# Generated by FakeRAM 2.0
VERSION 5.7 ;
BUSBITCHARS "[]" ;
PROPERTYDEFINITIONS
  MACRO width INTEGER ;
  MACRO depth INTEGER ;
  MACRO banks INTEGER ;
END PROPERTYDEFINITIONS
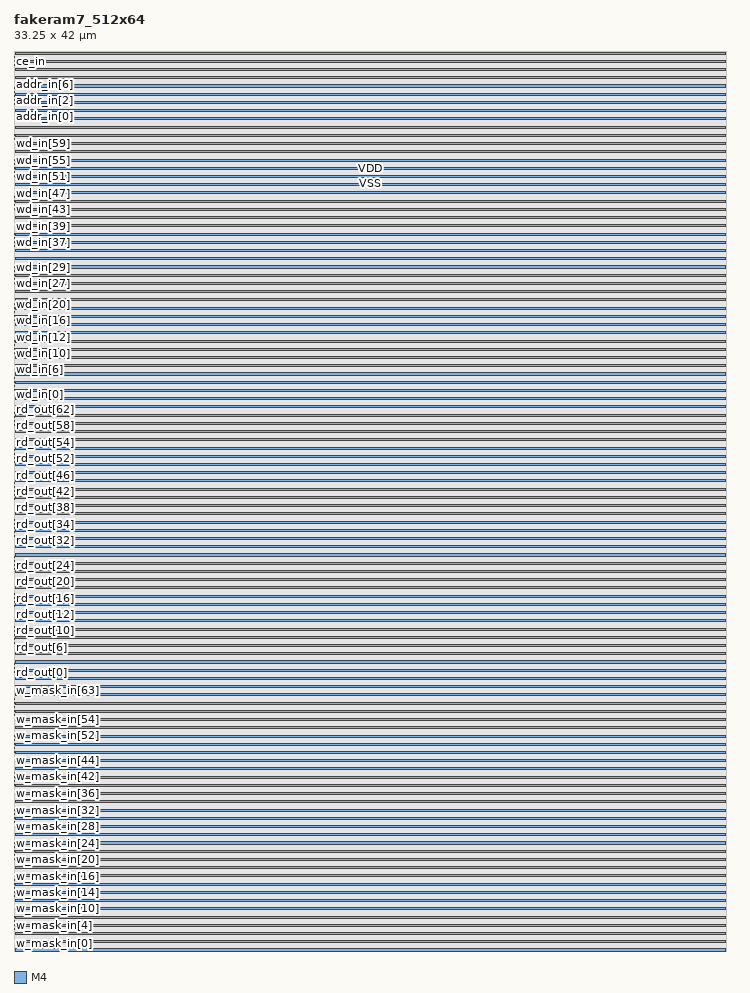
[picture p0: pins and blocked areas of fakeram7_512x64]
MACRO fakeram7_512x64
  PROPERTY width 64 ;
  PROPERTY depth 512 ;
  PROPERTY banks 4 ;
  FOREIGN fakeram7_512x64 0 0 ;
  SYMMETRY X Y ;
  SIZE 33.250 BY 42.000 ;
  CLASS BLOCK ;
  PIN w_mask_in[0]
    DIRECTION INPUT ;
    USE SIGNAL ;
    SHAPE ABUTMENT ;
    PORT
      LAYER M4 ;
      RECT 0.000 0.048 0.024 0.072 ;
    END
  END w_mask_in[0]
  PIN w_mask_in[1]
    DIRECTION INPUT ;
    USE SIGNAL ;
    SHAPE ABUTMENT ;
    PORT
      LAYER M4 ;
      RECT 0.000 0.240 0.024 0.264 ;
    END
  END w_mask_in[1]
  PIN w_mask_in[2]
    DIRECTION INPUT ;
    USE SIGNAL ;
    SHAPE ABUTMENT ;
    PORT
      LAYER M4 ;
      RECT 0.000 0.432 0.024 0.456 ;
    END
  END w_mask_in[2]
  PIN w_mask_in[3]
    DIRECTION INPUT ;
    USE SIGNAL ;
    SHAPE ABUTMENT ;
    PORT
      LAYER M4 ;
      RECT 0.000 0.624 0.024 0.648 ;
    END
  END w_mask_in[3]
  PIN w_mask_in[4]
    DIRECTION INPUT ;
    USE SIGNAL ;
    SHAPE ABUTMENT ;
    PORT
      LAYER M4 ;
      RECT 0.000 0.816 0.024 0.840 ;
    END
  END w_mask_in[4]
  PIN w_mask_in[5]
    DIRECTION INPUT ;
    USE SIGNAL ;
    SHAPE ABUTMENT ;
    PORT
      LAYER M4 ;
      RECT 0.000 1.008 0.024 1.032 ;
    END
  END w_mask_in[5]
  PIN w_mask_in[6]
    DIRECTION INPUT ;
    USE SIGNAL ;
    SHAPE ABUTMENT ;
    PORT
      LAYER M4 ;
      RECT 0.000 1.200 0.024 1.224 ;
    END
  END w_mask_in[6]
  PIN w_mask_in[7]
    DIRECTION INPUT ;
    USE SIGNAL ;
    SHAPE ABUTMENT ;
    PORT
      LAYER M4 ;
      RECT 0.000 1.392 0.024 1.416 ;
    END
  END w_mask_in[7]
  PIN w_mask_in[8]
    DIRECTION INPUT ;
    USE SIGNAL ;
    SHAPE ABUTMENT ;
    PORT
      LAYER M4 ;
      RECT 0.000 1.584 0.024 1.608 ;
    END
  END w_mask_in[8]
  PIN w_mask_in[9]
    DIRECTION INPUT ;
    USE SIGNAL ;
    SHAPE ABUTMENT ;
    PORT
      LAYER M4 ;
      RECT 0.000 1.776 0.024 1.800 ;
    END
  END w_mask_in[9]
  PIN w_mask_in[10]
    DIRECTION INPUT ;
    USE SIGNAL ;
    SHAPE ABUTMENT ;
    PORT
      LAYER M4 ;
      RECT 0.000 1.968 0.024 1.992 ;
    END
  END w_mask_in[10]
  PIN w_mask_in[11]
    DIRECTION INPUT ;
    USE SIGNAL ;
    SHAPE ABUTMENT ;
    PORT
      LAYER M4 ;
      RECT 0.000 2.160 0.024 2.184 ;
    END
  END w_mask_in[11]
  PIN w_mask_in[12]
    DIRECTION INPUT ;
    USE SIGNAL ;
    SHAPE ABUTMENT ;
    PORT
      LAYER M4 ;
      RECT 0.000 2.352 0.024 2.376 ;
    END
  END w_mask_in[12]
  PIN w_mask_in[13]
    DIRECTION INPUT ;
    USE SIGNAL ;
    SHAPE ABUTMENT ;
    PORT
      LAYER M4 ;
      RECT 0.000 2.544 0.024 2.568 ;
    END
  END w_mask_in[13]
  PIN w_mask_in[14]
    DIRECTION INPUT ;
    USE SIGNAL ;
    SHAPE ABUTMENT ;
    PORT
      LAYER M4 ;
      RECT 0.000 2.736 0.024 2.760 ;
    END
  END w_mask_in[14]
  PIN w_mask_in[15]
    DIRECTION INPUT ;
    USE SIGNAL ;
    SHAPE ABUTMENT ;
    PORT
      LAYER M4 ;
      RECT 0.000 2.928 0.024 2.952 ;
    END
  END w_mask_in[15]
  PIN w_mask_in[16]
    DIRECTION INPUT ;
    USE SIGNAL ;
    SHAPE ABUTMENT ;
    PORT
      LAYER M4 ;
      RECT 0.000 3.120 0.024 3.144 ;
    END
  END w_mask_in[16]
  PIN w_mask_in[17]
    DIRECTION INPUT ;
    USE SIGNAL ;
    SHAPE ABUTMENT ;
    PORT
      LAYER M4 ;
      RECT 0.000 3.312 0.024 3.336 ;
    END
  END w_mask_in[17]
  PIN w_mask_in[18]
    DIRECTION INPUT ;
    USE SIGNAL ;
    SHAPE ABUTMENT ;
    PORT
      LAYER M4 ;
      RECT 0.000 3.504 0.024 3.528 ;
    END
  END w_mask_in[18]
  PIN w_mask_in[19]
    DIRECTION INPUT ;
    USE SIGNAL ;
    SHAPE ABUTMENT ;
    PORT
      LAYER M4 ;
      RECT 0.000 3.696 0.024 3.720 ;
    END
  END w_mask_in[19]
  PIN w_mask_in[20]
    DIRECTION INPUT ;
    USE SIGNAL ;
    SHAPE ABUTMENT ;
    PORT
      LAYER M4 ;
      RECT 0.000 3.888 0.024 3.912 ;
    END
  END w_mask_in[20]
  PIN w_mask_in[21]
    DIRECTION INPUT ;
    USE SIGNAL ;
    SHAPE ABUTMENT ;
    PORT
      LAYER M4 ;
      RECT 0.000 4.080 0.024 4.104 ;
    END
  END w_mask_in[21]
  PIN w_mask_in[22]
    DIRECTION INPUT ;
    USE SIGNAL ;
    SHAPE ABUTMENT ;
    PORT
      LAYER M4 ;
      RECT 0.000 4.272 0.024 4.296 ;
    END
  END w_mask_in[22]
  PIN w_mask_in[23]
    DIRECTION INPUT ;
    USE SIGNAL ;
    SHAPE ABUTMENT ;
    PORT
      LAYER M4 ;
      RECT 0.000 4.464 0.024 4.488 ;
    END
  END w_mask_in[23]
  PIN w_mask_in[24]
    DIRECTION INPUT ;
    USE SIGNAL ;
    SHAPE ABUTMENT ;
    PORT
      LAYER M4 ;
      RECT 0.000 4.656 0.024 4.680 ;
    END
  END w_mask_in[24]
  PIN w_mask_in[25]
    DIRECTION INPUT ;
    USE SIGNAL ;
    SHAPE ABUTMENT ;
    PORT
      LAYER M4 ;
      RECT 0.000 4.848 0.024 4.872 ;
    END
  END w_mask_in[25]
  PIN w_mask_in[26]
    DIRECTION INPUT ;
    USE SIGNAL ;
    SHAPE ABUTMENT ;
    PORT
      LAYER M4 ;
      RECT 0.000 5.040 0.024 5.064 ;
    END
  END w_mask_in[26]
  PIN w_mask_in[27]
    DIRECTION INPUT ;
    USE SIGNAL ;
    SHAPE ABUTMENT ;
    PORT
      LAYER M4 ;
      RECT 0.000 5.232 0.024 5.256 ;
    END
  END w_mask_in[27]
  PIN w_mask_in[28]
    DIRECTION INPUT ;
    USE SIGNAL ;
    SHAPE ABUTMENT ;
    PORT
      LAYER M4 ;
      RECT 0.000 5.424 0.024 5.448 ;
    END
  END w_mask_in[28]
  PIN w_mask_in[29]
    DIRECTION INPUT ;
    USE SIGNAL ;
    SHAPE ABUTMENT ;
    PORT
      LAYER M4 ;
      RECT 0.000 5.616 0.024 5.640 ;
    END
  END w_mask_in[29]
  PIN w_mask_in[30]
    DIRECTION INPUT ;
    USE SIGNAL ;
    SHAPE ABUTMENT ;
    PORT
      LAYER M4 ;
      RECT 0.000 5.808 0.024 5.832 ;
    END
  END w_mask_in[30]
  PIN w_mask_in[31]
    DIRECTION INPUT ;
    USE SIGNAL ;
    SHAPE ABUTMENT ;
    PORT
      LAYER M4 ;
      RECT 0.000 6.000 0.024 6.024 ;
    END
  END w_mask_in[31]
  PIN w_mask_in[32]
    DIRECTION INPUT ;
    USE SIGNAL ;
    SHAPE ABUTMENT ;
    PORT
      LAYER M4 ;
      RECT 0.000 6.192 0.024 6.216 ;
    END
  END w_mask_in[32]
  PIN w_mask_in[33]
    DIRECTION INPUT ;
    USE SIGNAL ;
    SHAPE ABUTMENT ;
    PORT
      LAYER M4 ;
      RECT 0.000 6.384 0.024 6.408 ;
    END
  END w_mask_in[33]
  PIN w_mask_in[34]
    DIRECTION INPUT ;
    USE SIGNAL ;
    SHAPE ABUTMENT ;
    PORT
      LAYER M4 ;
      RECT 0.000 6.576 0.024 6.600 ;
    END
  END w_mask_in[34]
  PIN w_mask_in[35]
    DIRECTION INPUT ;
    USE SIGNAL ;
    SHAPE ABUTMENT ;
    PORT
      LAYER M4 ;
      RECT 0.000 6.768 0.024 6.792 ;
    END
  END w_mask_in[35]
  PIN w_mask_in[36]
    DIRECTION INPUT ;
    USE SIGNAL ;
    SHAPE ABUTMENT ;
    PORT
      LAYER M4 ;
      RECT 0.000 6.960 0.024 6.984 ;
    END
  END w_mask_in[36]
  PIN w_mask_in[37]
    DIRECTION INPUT ;
    USE SIGNAL ;
    SHAPE ABUTMENT ;
    PORT
      LAYER M4 ;
      RECT 0.000 7.152 0.024 7.176 ;
    END
  END w_mask_in[37]
  PIN w_mask_in[38]
    DIRECTION INPUT ;
    USE SIGNAL ;
    SHAPE ABUTMENT ;
    PORT
      LAYER M4 ;
      RECT 0.000 7.344 0.024 7.368 ;
    END
  END w_mask_in[38]
  PIN w_mask_in[39]
    DIRECTION INPUT ;
    USE SIGNAL ;
    SHAPE ABUTMENT ;
    PORT
      LAYER M4 ;
      RECT 0.000 7.536 0.024 7.560 ;
    END
  END w_mask_in[39]
  PIN w_mask_in[40]
    DIRECTION INPUT ;
    USE SIGNAL ;
    SHAPE ABUTMENT ;
    PORT
      LAYER M4 ;
      RECT 0.000 7.728 0.024 7.752 ;
    END
  END w_mask_in[40]
  PIN w_mask_in[41]
    DIRECTION INPUT ;
    USE SIGNAL ;
    SHAPE ABUTMENT ;
    PORT
      LAYER M4 ;
      RECT 0.000 7.920 0.024 7.944 ;
    END
  END w_mask_in[41]
  PIN w_mask_in[42]
    DIRECTION INPUT ;
    USE SIGNAL ;
    SHAPE ABUTMENT ;
    PORT
      LAYER M4 ;
      RECT 0.000 8.112 0.024 8.136 ;
    END
  END w_mask_in[42]
  PIN w_mask_in[43]
    DIRECTION INPUT ;
    USE SIGNAL ;
    SHAPE ABUTMENT ;
    PORT
      LAYER M4 ;
      RECT 0.000 8.304 0.024 8.328 ;
    END
  END w_mask_in[43]
  PIN w_mask_in[44]
    DIRECTION INPUT ;
    USE SIGNAL ;
    SHAPE ABUTMENT ;
    PORT
      LAYER M4 ;
      RECT 0.000 8.496 0.024 8.520 ;
    END
  END w_mask_in[44]
  PIN w_mask_in[45]
    DIRECTION INPUT ;
    USE SIGNAL ;
    SHAPE ABUTMENT ;
    PORT
      LAYER M4 ;
      RECT 0.000 8.688 0.024 8.712 ;
    END
  END w_mask_in[45]
  PIN w_mask_in[46]
    DIRECTION INPUT ;
    USE SIGNAL ;
    SHAPE ABUTMENT ;
    PORT
      LAYER M4 ;
      RECT 0.000 8.880 0.024 8.904 ;
    END
  END w_mask_in[46]
  PIN w_mask_in[47]
    DIRECTION INPUT ;
    USE SIGNAL ;
    SHAPE ABUTMENT ;
    PORT
      LAYER M4 ;
      RECT 0.000 9.072 0.024 9.096 ;
    END
  END w_mask_in[47]
  PIN w_mask_in[48]
    DIRECTION INPUT ;
    USE SIGNAL ;
    SHAPE ABUTMENT ;
    PORT
      LAYER M4 ;
      RECT 0.000 9.264 0.024 9.288 ;
    END
  END w_mask_in[48]
  PIN w_mask_in[49]
    DIRECTION INPUT ;
    USE SIGNAL ;
    SHAPE ABUTMENT ;
    PORT
      LAYER M4 ;
      RECT 0.000 9.456 0.024 9.480 ;
    END
  END w_mask_in[49]
  PIN w_mask_in[50]
    DIRECTION INPUT ;
    USE SIGNAL ;
    SHAPE ABUTMENT ;
    PORT
      LAYER M4 ;
      RECT 0.000 9.648 0.024 9.672 ;
    END
  END w_mask_in[50]
  PIN w_mask_in[51]
    DIRECTION INPUT ;
    USE SIGNAL ;
    SHAPE ABUTMENT ;
    PORT
      LAYER M4 ;
      RECT 0.000 9.840 0.024 9.864 ;
    END
  END w_mask_in[51]
  PIN w_mask_in[52]
    DIRECTION INPUT ;
    USE SIGNAL ;
    SHAPE ABUTMENT ;
    PORT
      LAYER M4 ;
      RECT 0.000 10.032 0.024 10.056 ;
    END
  END w_mask_in[52]
  PIN w_mask_in[53]
    DIRECTION INPUT ;
    USE SIGNAL ;
    SHAPE ABUTMENT ;
    PORT
      LAYER M4 ;
      RECT 0.000 10.224 0.024 10.248 ;
    END
  END w_mask_in[53]
  PIN w_mask_in[54]
    DIRECTION INPUT ;
    USE SIGNAL ;
    SHAPE ABUTMENT ;
    PORT
      LAYER M4 ;
      RECT 0.000 10.416 0.024 10.440 ;
    END
  END w_mask_in[54]
  PIN w_mask_in[55]
    DIRECTION INPUT ;
    USE SIGNAL ;
    SHAPE ABUTMENT ;
    PORT
      LAYER M4 ;
      RECT 0.000 10.608 0.024 10.632 ;
    END
  END w_mask_in[55]
  PIN w_mask_in[56]
    DIRECTION INPUT ;
    USE SIGNAL ;
    SHAPE ABUTMENT ;
    PORT
      LAYER M4 ;
      RECT 0.000 10.800 0.024 10.824 ;
    END
  END w_mask_in[56]
  PIN w_mask_in[57]
    DIRECTION INPUT ;
    USE SIGNAL ;
    SHAPE ABUTMENT ;
    PORT
      LAYER M4 ;
      RECT 0.000 10.992 0.024 11.016 ;
    END
  END w_mask_in[57]
  PIN w_mask_in[58]
    DIRECTION INPUT ;
    USE SIGNAL ;
    SHAPE ABUTMENT ;
    PORT
      LAYER M4 ;
      RECT 0.000 11.184 0.024 11.208 ;
    END
  END w_mask_in[58]
  PIN w_mask_in[59]
    DIRECTION INPUT ;
    USE SIGNAL ;
    SHAPE ABUTMENT ;
    PORT
      LAYER M4 ;
      RECT 0.000 11.376 0.024 11.400 ;
    END
  END w_mask_in[59]
  PIN w_mask_in[60]
    DIRECTION INPUT ;
    USE SIGNAL ;
    SHAPE ABUTMENT ;
    PORT
      LAYER M4 ;
      RECT 0.000 11.568 0.024 11.592 ;
    END
  END w_mask_in[60]
  PIN w_mask_in[61]
    DIRECTION INPUT ;
    USE SIGNAL ;
    SHAPE ABUTMENT ;
    PORT
      LAYER M4 ;
      RECT 0.000 11.760 0.024 11.784 ;
    END
  END w_mask_in[61]
  PIN w_mask_in[62]
    DIRECTION INPUT ;
    USE SIGNAL ;
    SHAPE ABUTMENT ;
    PORT
      LAYER M4 ;
      RECT 0.000 11.952 0.024 11.976 ;
    END
  END w_mask_in[62]
  PIN w_mask_in[63]
    DIRECTION INPUT ;
    USE SIGNAL ;
    SHAPE ABUTMENT ;
    PORT
      LAYER M4 ;
      RECT 0.000 12.144 0.024 12.168 ;
    END
  END w_mask_in[63]
  PIN rd_out[0]
    DIRECTION OUTPUT ;
    USE SIGNAL ;
    SHAPE ABUTMENT ;
    PORT
      LAYER M4 ;
      RECT 0.000 13.008 0.024 13.032 ;
    END
  END rd_out[0]
  PIN rd_out[1]
    DIRECTION OUTPUT ;
    USE SIGNAL ;
    SHAPE ABUTMENT ;
    PORT
      LAYER M4 ;
      RECT 0.000 13.200 0.024 13.224 ;
    END
  END rd_out[1]
  PIN rd_out[2]
    DIRECTION OUTPUT ;
    USE SIGNAL ;
    SHAPE ABUTMENT ;
    PORT
      LAYER M4 ;
      RECT 0.000 13.392 0.024 13.416 ;
    END
  END rd_out[2]
  PIN rd_out[3]
    DIRECTION OUTPUT ;
    USE SIGNAL ;
    SHAPE ABUTMENT ;
    PORT
      LAYER M4 ;
      RECT 0.000 13.584 0.024 13.608 ;
    END
  END rd_out[3]
  PIN rd_out[4]
    DIRECTION OUTPUT ;
    USE SIGNAL ;
    SHAPE ABUTMENT ;
    PORT
      LAYER M4 ;
      RECT 0.000 13.776 0.024 13.800 ;
    END
  END rd_out[4]
  PIN rd_out[5]
    DIRECTION OUTPUT ;
    USE SIGNAL ;
    SHAPE ABUTMENT ;
    PORT
      LAYER M4 ;
      RECT 0.000 13.968 0.024 13.992 ;
    END
  END rd_out[5]
  PIN rd_out[6]
    DIRECTION OUTPUT ;
    USE SIGNAL ;
    SHAPE ABUTMENT ;
    PORT
      LAYER M4 ;
      RECT 0.000 14.160 0.024 14.184 ;
    END
  END rd_out[6]
  PIN rd_out[7]
    DIRECTION OUTPUT ;
    USE SIGNAL ;
    SHAPE ABUTMENT ;
    PORT
      LAYER M4 ;
      RECT 0.000 14.352 0.024 14.376 ;
    END
  END rd_out[7]
  PIN rd_out[8]
    DIRECTION OUTPUT ;
    USE SIGNAL ;
    SHAPE ABUTMENT ;
    PORT
      LAYER M4 ;
      RECT 0.000 14.544 0.024 14.568 ;
    END
  END rd_out[8]
  PIN rd_out[9]
    DIRECTION OUTPUT ;
    USE SIGNAL ;
    SHAPE ABUTMENT ;
    PORT
      LAYER M4 ;
      RECT 0.000 14.736 0.024 14.760 ;
    END
  END rd_out[9]
  PIN rd_out[10]
    DIRECTION OUTPUT ;
    USE SIGNAL ;
    SHAPE ABUTMENT ;
    PORT
      LAYER M4 ;
      RECT 0.000 14.928 0.024 14.952 ;
    END
  END rd_out[10]
  PIN rd_out[11]
    DIRECTION OUTPUT ;
    USE SIGNAL ;
    SHAPE ABUTMENT ;
    PORT
      LAYER M4 ;
      RECT 0.000 15.120 0.024 15.144 ;
    END
  END rd_out[11]
  PIN rd_out[12]
    DIRECTION OUTPUT ;
    USE SIGNAL ;
    SHAPE ABUTMENT ;
    PORT
      LAYER M4 ;
      RECT 0.000 15.312 0.024 15.336 ;
    END
  END rd_out[12]
  PIN rd_out[13]
    DIRECTION OUTPUT ;
    USE SIGNAL ;
    SHAPE ABUTMENT ;
    PORT
      LAYER M4 ;
      RECT 0.000 15.504 0.024 15.528 ;
    END
  END rd_out[13]
  PIN rd_out[14]
    DIRECTION OUTPUT ;
    USE SIGNAL ;
    SHAPE ABUTMENT ;
    PORT
      LAYER M4 ;
      RECT 0.000 15.696 0.024 15.720 ;
    END
  END rd_out[14]
  PIN rd_out[15]
    DIRECTION OUTPUT ;
    USE SIGNAL ;
    SHAPE ABUTMENT ;
    PORT
      LAYER M4 ;
      RECT 0.000 15.888 0.024 15.912 ;
    END
  END rd_out[15]
  PIN rd_out[16]
    DIRECTION OUTPUT ;
    USE SIGNAL ;
    SHAPE ABUTMENT ;
    PORT
      LAYER M4 ;
      RECT 0.000 16.080 0.024 16.104 ;
    END
  END rd_out[16]
  PIN rd_out[17]
    DIRECTION OUTPUT ;
    USE SIGNAL ;
    SHAPE ABUTMENT ;
    PORT
      LAYER M4 ;
      RECT 0.000 16.272 0.024 16.296 ;
    END
  END rd_out[17]
  PIN rd_out[18]
    DIRECTION OUTPUT ;
    USE SIGNAL ;
    SHAPE ABUTMENT ;
    PORT
      LAYER M4 ;
      RECT 0.000 16.464 0.024 16.488 ;
    END
  END rd_out[18]
  PIN rd_out[19]
    DIRECTION OUTPUT ;
    USE SIGNAL ;
    SHAPE ABUTMENT ;
    PORT
      LAYER M4 ;
      RECT 0.000 16.656 0.024 16.680 ;
    END
  END rd_out[19]
  PIN rd_out[20]
    DIRECTION OUTPUT ;
    USE SIGNAL ;
    SHAPE ABUTMENT ;
    PORT
      LAYER M4 ;
      RECT 0.000 16.848 0.024 16.872 ;
    END
  END rd_out[20]
  PIN rd_out[21]
    DIRECTION OUTPUT ;
    USE SIGNAL ;
    SHAPE ABUTMENT ;
    PORT
      LAYER M4 ;
      RECT 0.000 17.040 0.024 17.064 ;
    END
  END rd_out[21]
  PIN rd_out[22]
    DIRECTION OUTPUT ;
    USE SIGNAL ;
    SHAPE ABUTMENT ;
    PORT
      LAYER M4 ;
      RECT 0.000 17.232 0.024 17.256 ;
    END
  END rd_out[22]
  PIN rd_out[23]
    DIRECTION OUTPUT ;
    USE SIGNAL ;
    SHAPE ABUTMENT ;
    PORT
      LAYER M4 ;
      RECT 0.000 17.424 0.024 17.448 ;
    END
  END rd_out[23]
  PIN rd_out[24]
    DIRECTION OUTPUT ;
    USE SIGNAL ;
    SHAPE ABUTMENT ;
    PORT
      LAYER M4 ;
      RECT 0.000 17.616 0.024 17.640 ;
    END
  END rd_out[24]
  PIN rd_out[25]
    DIRECTION OUTPUT ;
    USE SIGNAL ;
    SHAPE ABUTMENT ;
    PORT
      LAYER M4 ;
      RECT 0.000 17.808 0.024 17.832 ;
    END
  END rd_out[25]
  PIN rd_out[26]
    DIRECTION OUTPUT ;
    USE SIGNAL ;
    SHAPE ABUTMENT ;
    PORT
      LAYER M4 ;
      RECT 0.000 18.000 0.024 18.024 ;
    END
  END rd_out[26]
  PIN rd_out[27]
    DIRECTION OUTPUT ;
    USE SIGNAL ;
    SHAPE ABUTMENT ;
    PORT
      LAYER M4 ;
      RECT 0.000 18.192 0.024 18.216 ;
    END
  END rd_out[27]
  PIN rd_out[28]
    DIRECTION OUTPUT ;
    USE SIGNAL ;
    SHAPE ABUTMENT ;
    PORT
      LAYER M4 ;
      RECT 0.000 18.384 0.024 18.408 ;
    END
  END rd_out[28]
  PIN rd_out[29]
    DIRECTION OUTPUT ;
    USE SIGNAL ;
    SHAPE ABUTMENT ;
    PORT
      LAYER M4 ;
      RECT 0.000 18.576 0.024 18.600 ;
    END
  END rd_out[29]
  PIN rd_out[30]
    DIRECTION OUTPUT ;
    USE SIGNAL ;
    SHAPE ABUTMENT ;
    PORT
      LAYER M4 ;
      RECT 0.000 18.768 0.024 18.792 ;
    END
  END rd_out[30]
  PIN rd_out[31]
    DIRECTION OUTPUT ;
    USE SIGNAL ;
    SHAPE ABUTMENT ;
    PORT
      LAYER M4 ;
      RECT 0.000 18.960 0.024 18.984 ;
    END
  END rd_out[31]
  PIN rd_out[32]
    DIRECTION OUTPUT ;
    USE SIGNAL ;
    SHAPE ABUTMENT ;
    PORT
      LAYER M4 ;
      RECT 0.000 19.152 0.024 19.176 ;
    END
  END rd_out[32]
  PIN rd_out[33]
    DIRECTION OUTPUT ;
    USE SIGNAL ;
    SHAPE ABUTMENT ;
    PORT
      LAYER M4 ;
      RECT 0.000 19.344 0.024 19.368 ;
    END
  END rd_out[33]
  PIN rd_out[34]
    DIRECTION OUTPUT ;
    USE SIGNAL ;
    SHAPE ABUTMENT ;
    PORT
      LAYER M4 ;
      RECT 0.000 19.536 0.024 19.560 ;
    END
  END rd_out[34]
  PIN rd_out[35]
    DIRECTION OUTPUT ;
    USE SIGNAL ;
    SHAPE ABUTMENT ;
    PORT
      LAYER M4 ;
      RECT 0.000 19.728 0.024 19.752 ;
    END
  END rd_out[35]
  PIN rd_out[36]
    DIRECTION OUTPUT ;
    USE SIGNAL ;
    SHAPE ABUTMENT ;
    PORT
      LAYER M4 ;
      RECT 0.000 19.920 0.024 19.944 ;
    END
  END rd_out[36]
  PIN rd_out[37]
    DIRECTION OUTPUT ;
    USE SIGNAL ;
    SHAPE ABUTMENT ;
    PORT
      LAYER M4 ;
      RECT 0.000 20.112 0.024 20.136 ;
    END
  END rd_out[37]
  PIN rd_out[38]
    DIRECTION OUTPUT ;
    USE SIGNAL ;
    SHAPE ABUTMENT ;
    PORT
      LAYER M4 ;
      RECT 0.000 20.304 0.024 20.328 ;
    END
  END rd_out[38]
  PIN rd_out[39]
    DIRECTION OUTPUT ;
    USE SIGNAL ;
    SHAPE ABUTMENT ;
    PORT
      LAYER M4 ;
      RECT 0.000 20.496 0.024 20.520 ;
    END
  END rd_out[39]
  PIN rd_out[40]
    DIRECTION OUTPUT ;
    USE SIGNAL ;
    SHAPE ABUTMENT ;
    PORT
      LAYER M4 ;
      RECT 0.000 20.688 0.024 20.712 ;
    END
  END rd_out[40]
  PIN rd_out[41]
    DIRECTION OUTPUT ;
    USE SIGNAL ;
    SHAPE ABUTMENT ;
    PORT
      LAYER M4 ;
      RECT 0.000 20.880 0.024 20.904 ;
    END
  END rd_out[41]
  PIN rd_out[42]
    DIRECTION OUTPUT ;
    USE SIGNAL ;
    SHAPE ABUTMENT ;
    PORT
      LAYER M4 ;
      RECT 0.000 21.072 0.024 21.096 ;
    END
  END rd_out[42]
  PIN rd_out[43]
    DIRECTION OUTPUT ;
    USE SIGNAL ;
    SHAPE ABUTMENT ;
    PORT
      LAYER M4 ;
      RECT 0.000 21.264 0.024 21.288 ;
    END
  END rd_out[43]
  PIN rd_out[44]
    DIRECTION OUTPUT ;
    USE SIGNAL ;
    SHAPE ABUTMENT ;
    PORT
      LAYER M4 ;
      RECT 0.000 21.456 0.024 21.480 ;
    END
  END rd_out[44]
  PIN rd_out[45]
    DIRECTION OUTPUT ;
    USE SIGNAL ;
    SHAPE ABUTMENT ;
    PORT
      LAYER M4 ;
      RECT 0.000 21.648 0.024 21.672 ;
    END
  END rd_out[45]
  PIN rd_out[46]
    DIRECTION OUTPUT ;
    USE SIGNAL ;
    SHAPE ABUTMENT ;
    PORT
      LAYER M4 ;
      RECT 0.000 21.840 0.024 21.864 ;
    END
  END rd_out[46]
  PIN rd_out[47]
    DIRECTION OUTPUT ;
    USE SIGNAL ;
    SHAPE ABUTMENT ;
    PORT
      LAYER M4 ;
      RECT 0.000 22.032 0.024 22.056 ;
    END
  END rd_out[47]
  PIN rd_out[48]
    DIRECTION OUTPUT ;
    USE SIGNAL ;
    SHAPE ABUTMENT ;
    PORT
      LAYER M4 ;
      RECT 0.000 22.224 0.024 22.248 ;
    END
  END rd_out[48]
  PIN rd_out[49]
    DIRECTION OUTPUT ;
    USE SIGNAL ;
    SHAPE ABUTMENT ;
    PORT
      LAYER M4 ;
      RECT 0.000 22.416 0.024 22.440 ;
    END
  END rd_out[49]
  PIN rd_out[50]
    DIRECTION OUTPUT ;
    USE SIGNAL ;
    SHAPE ABUTMENT ;
    PORT
      LAYER M4 ;
      RECT 0.000 22.608 0.024 22.632 ;
    END
  END rd_out[50]
  PIN rd_out[51]
    DIRECTION OUTPUT ;
    USE SIGNAL ;
    SHAPE ABUTMENT ;
    PORT
      LAYER M4 ;
      RECT 0.000 22.800 0.024 22.824 ;
    END
  END rd_out[51]
  PIN rd_out[52]
    DIRECTION OUTPUT ;
    USE SIGNAL ;
    SHAPE ABUTMENT ;
    PORT
      LAYER M4 ;
      RECT 0.000 22.992 0.024 23.016 ;
    END
  END rd_out[52]
  PIN rd_out[53]
    DIRECTION OUTPUT ;
    USE SIGNAL ;
    SHAPE ABUTMENT ;
    PORT
      LAYER M4 ;
      RECT 0.000 23.184 0.024 23.208 ;
    END
  END rd_out[53]
  PIN rd_out[54]
    DIRECTION OUTPUT ;
    USE SIGNAL ;
    SHAPE ABUTMENT ;
    PORT
      LAYER M4 ;
      RECT 0.000 23.376 0.024 23.400 ;
    END
  END rd_out[54]
  PIN rd_out[55]
    DIRECTION OUTPUT ;
    USE SIGNAL ;
    SHAPE ABUTMENT ;
    PORT
      LAYER M4 ;
      RECT 0.000 23.568 0.024 23.592 ;
    END
  END rd_out[55]
  PIN rd_out[56]
    DIRECTION OUTPUT ;
    USE SIGNAL ;
    SHAPE ABUTMENT ;
    PORT
      LAYER M4 ;
      RECT 0.000 23.760 0.024 23.784 ;
    END
  END rd_out[56]
  PIN rd_out[57]
    DIRECTION OUTPUT ;
    USE SIGNAL ;
    SHAPE ABUTMENT ;
    PORT
      LAYER M4 ;
      RECT 0.000 23.952 0.024 23.976 ;
    END
  END rd_out[57]
  PIN rd_out[58]
    DIRECTION OUTPUT ;
    USE SIGNAL ;
    SHAPE ABUTMENT ;
    PORT
      LAYER M4 ;
      RECT 0.000 24.144 0.024 24.168 ;
    END
  END rd_out[58]
  PIN rd_out[59]
    DIRECTION OUTPUT ;
    USE SIGNAL ;
    SHAPE ABUTMENT ;
    PORT
      LAYER M4 ;
      RECT 0.000 24.336 0.024 24.360 ;
    END
  END rd_out[59]
  PIN rd_out[60]
    DIRECTION OUTPUT ;
    USE SIGNAL ;
    SHAPE ABUTMENT ;
    PORT
      LAYER M4 ;
      RECT 0.000 24.528 0.024 24.552 ;
    END
  END rd_out[60]
  PIN rd_out[61]
    DIRECTION OUTPUT ;
    USE SIGNAL ;
    SHAPE ABUTMENT ;
    PORT
      LAYER M4 ;
      RECT 0.000 24.720 0.024 24.744 ;
    END
  END rd_out[61]
  PIN rd_out[62]
    DIRECTION OUTPUT ;
    USE SIGNAL ;
    SHAPE ABUTMENT ;
    PORT
      LAYER M4 ;
      RECT 0.000 24.912 0.024 24.936 ;
    END
  END rd_out[62]
  PIN rd_out[63]
    DIRECTION OUTPUT ;
    USE SIGNAL ;
    SHAPE ABUTMENT ;
    PORT
      LAYER M4 ;
      RECT 0.000 25.104 0.024 25.128 ;
    END
  END rd_out[63]
  PIN wd_in[0]
    DIRECTION INPUT ;
    USE SIGNAL ;
    SHAPE ABUTMENT ;
    PORT
      LAYER M4 ;
      RECT 0.000 25.968 0.024 25.992 ;
    END
  END wd_in[0]
  PIN wd_in[1]
    DIRECTION INPUT ;
    USE SIGNAL ;
    SHAPE ABUTMENT ;
    PORT
      LAYER M4 ;
      RECT 0.000 26.160 0.024 26.184 ;
    END
  END wd_in[1]
  PIN wd_in[2]
    DIRECTION INPUT ;
    USE SIGNAL ;
    SHAPE ABUTMENT ;
    PORT
      LAYER M4 ;
      RECT 0.000 26.352 0.024 26.376 ;
    END
  END wd_in[2]
  PIN wd_in[3]
    DIRECTION INPUT ;
    USE SIGNAL ;
    SHAPE ABUTMENT ;
    PORT
      LAYER M4 ;
      RECT 0.000 26.544 0.024 26.568 ;
    END
  END wd_in[3]
  PIN wd_in[4]
    DIRECTION INPUT ;
    USE SIGNAL ;
    SHAPE ABUTMENT ;
    PORT
      LAYER M4 ;
      RECT 0.000 26.736 0.024 26.760 ;
    END
  END wd_in[4]
  PIN wd_in[5]
    DIRECTION INPUT ;
    USE SIGNAL ;
    SHAPE ABUTMENT ;
    PORT
      LAYER M4 ;
      RECT 0.000 26.928 0.024 26.952 ;
    END
  END wd_in[5]
  PIN wd_in[6]
    DIRECTION INPUT ;
    USE SIGNAL ;
    SHAPE ABUTMENT ;
    PORT
      LAYER M4 ;
      RECT 0.000 27.120 0.024 27.144 ;
    END
  END wd_in[6]
  PIN wd_in[7]
    DIRECTION INPUT ;
    USE SIGNAL ;
    SHAPE ABUTMENT ;
    PORT
      LAYER M4 ;
      RECT 0.000 27.312 0.024 27.336 ;
    END
  END wd_in[7]
  PIN wd_in[8]
    DIRECTION INPUT ;
    USE SIGNAL ;
    SHAPE ABUTMENT ;
    PORT
      LAYER M4 ;
      RECT 0.000 27.504 0.024 27.528 ;
    END
  END wd_in[8]
  PIN wd_in[9]
    DIRECTION INPUT ;
    USE SIGNAL ;
    SHAPE ABUTMENT ;
    PORT
      LAYER M4 ;
      RECT 0.000 27.696 0.024 27.720 ;
    END
  END wd_in[9]
  PIN wd_in[10]
    DIRECTION INPUT ;
    USE SIGNAL ;
    SHAPE ABUTMENT ;
    PORT
      LAYER M4 ;
      RECT 0.000 27.888 0.024 27.912 ;
    END
  END wd_in[10]
  PIN wd_in[11]
    DIRECTION INPUT ;
    USE SIGNAL ;
    SHAPE ABUTMENT ;
    PORT
      LAYER M4 ;
      RECT 0.000 28.080 0.024 28.104 ;
    END
  END wd_in[11]
  PIN wd_in[12]
    DIRECTION INPUT ;
    USE SIGNAL ;
    SHAPE ABUTMENT ;
    PORT
      LAYER M4 ;
      RECT 0.000 28.272 0.024 28.296 ;
    END
  END wd_in[12]
  PIN wd_in[13]
    DIRECTION INPUT ;
    USE SIGNAL ;
    SHAPE ABUTMENT ;
    PORT
      LAYER M4 ;
      RECT 0.000 28.464 0.024 28.488 ;
    END
  END wd_in[13]
  PIN wd_in[14]
    DIRECTION INPUT ;
    USE SIGNAL ;
    SHAPE ABUTMENT ;
    PORT
      LAYER M4 ;
      RECT 0.000 28.656 0.024 28.680 ;
    END
  END wd_in[14]
  PIN wd_in[15]
    DIRECTION INPUT ;
    USE SIGNAL ;
    SHAPE ABUTMENT ;
    PORT
      LAYER M4 ;
      RECT 0.000 28.848 0.024 28.872 ;
    END
  END wd_in[15]
  PIN wd_in[16]
    DIRECTION INPUT ;
    USE SIGNAL ;
    SHAPE ABUTMENT ;
    PORT
      LAYER M4 ;
      RECT 0.000 29.040 0.024 29.064 ;
    END
  END wd_in[16]
  PIN wd_in[17]
    DIRECTION INPUT ;
    USE SIGNAL ;
    SHAPE ABUTMENT ;
    PORT
      LAYER M4 ;
      RECT 0.000 29.232 0.024 29.256 ;
    END
  END wd_in[17]
  PIN wd_in[18]
    DIRECTION INPUT ;
    USE SIGNAL ;
    SHAPE ABUTMENT ;
    PORT
      LAYER M4 ;
      RECT 0.000 29.424 0.024 29.448 ;
    END
  END wd_in[18]
  PIN wd_in[19]
    DIRECTION INPUT ;
    USE SIGNAL ;
    SHAPE ABUTMENT ;
    PORT
      LAYER M4 ;
      RECT 0.000 29.616 0.024 29.640 ;
    END
  END wd_in[19]
  PIN wd_in[20]
    DIRECTION INPUT ;
    USE SIGNAL ;
    SHAPE ABUTMENT ;
    PORT
      LAYER M4 ;
      RECT 0.000 29.808 0.024 29.832 ;
    END
  END wd_in[20]
  PIN wd_in[21]
    DIRECTION INPUT ;
    USE SIGNAL ;
    SHAPE ABUTMENT ;
    PORT
      LAYER M4 ;
      RECT 0.000 30.000 0.024 30.024 ;
    END
  END wd_in[21]
  PIN wd_in[22]
    DIRECTION INPUT ;
    USE SIGNAL ;
    SHAPE ABUTMENT ;
    PORT
      LAYER M4 ;
      RECT 0.000 30.192 0.024 30.216 ;
    END
  END wd_in[22]
  PIN wd_in[23]
    DIRECTION INPUT ;
    USE SIGNAL ;
    SHAPE ABUTMENT ;
    PORT
      LAYER M4 ;
      RECT 0.000 30.384 0.024 30.408 ;
    END
  END wd_in[23]
  PIN wd_in[24]
    DIRECTION INPUT ;
    USE SIGNAL ;
    SHAPE ABUTMENT ;
    PORT
      LAYER M4 ;
      RECT 0.000 30.576 0.024 30.600 ;
    END
  END wd_in[24]
  PIN wd_in[25]
    DIRECTION INPUT ;
    USE SIGNAL ;
    SHAPE ABUTMENT ;
    PORT
      LAYER M4 ;
      RECT 0.000 30.768 0.024 30.792 ;
    END
  END wd_in[25]
  PIN wd_in[26]
    DIRECTION INPUT ;
    USE SIGNAL ;
    SHAPE ABUTMENT ;
    PORT
      LAYER M4 ;
      RECT 0.000 30.960 0.024 30.984 ;
    END
  END wd_in[26]
  PIN wd_in[27]
    DIRECTION INPUT ;
    USE SIGNAL ;
    SHAPE ABUTMENT ;
    PORT
      LAYER M4 ;
      RECT 0.000 31.152 0.024 31.176 ;
    END
  END wd_in[27]
  PIN wd_in[28]
    DIRECTION INPUT ;
    USE SIGNAL ;
    SHAPE ABUTMENT ;
    PORT
      LAYER M4 ;
      RECT 0.000 31.344 0.024 31.368 ;
    END
  END wd_in[28]
  PIN wd_in[29]
    DIRECTION INPUT ;
    USE SIGNAL ;
    SHAPE ABUTMENT ;
    PORT
      LAYER M4 ;
      RECT 0.000 31.536 0.024 31.560 ;
    END
  END wd_in[29]
  PIN wd_in[30]
    DIRECTION INPUT ;
    USE SIGNAL ;
    SHAPE ABUTMENT ;
    PORT
      LAYER M4 ;
      RECT 0.000 31.728 0.024 31.752 ;
    END
  END wd_in[30]
  PIN wd_in[31]
    DIRECTION INPUT ;
    USE SIGNAL ;
    SHAPE ABUTMENT ;
    PORT
      LAYER M4 ;
      RECT 0.000 31.920 0.024 31.944 ;
    END
  END wd_in[31]
  PIN wd_in[32]
    DIRECTION INPUT ;
    USE SIGNAL ;
    SHAPE ABUTMENT ;
    PORT
      LAYER M4 ;
      RECT 0.000 32.112 0.024 32.136 ;
    END
  END wd_in[32]
  PIN wd_in[33]
    DIRECTION INPUT ;
    USE SIGNAL ;
    SHAPE ABUTMENT ;
    PORT
      LAYER M4 ;
      RECT 0.000 32.304 0.024 32.328 ;
    END
  END wd_in[33]
  PIN wd_in[34]
    DIRECTION INPUT ;
    USE SIGNAL ;
    SHAPE ABUTMENT ;
    PORT
      LAYER M4 ;
      RECT 0.000 32.496 0.024 32.520 ;
    END
  END wd_in[34]
  PIN wd_in[35]
    DIRECTION INPUT ;
    USE SIGNAL ;
    SHAPE ABUTMENT ;
    PORT
      LAYER M4 ;
      RECT 0.000 32.688 0.024 32.712 ;
    END
  END wd_in[35]
  PIN wd_in[36]
    DIRECTION INPUT ;
    USE SIGNAL ;
    SHAPE ABUTMENT ;
    PORT
      LAYER M4 ;
      RECT 0.000 32.880 0.024 32.904 ;
    END
  END wd_in[36]
  PIN wd_in[37]
    DIRECTION INPUT ;
    USE SIGNAL ;
    SHAPE ABUTMENT ;
    PORT
      LAYER M4 ;
      RECT 0.000 33.072 0.024 33.096 ;
    END
  END wd_in[37]
  PIN wd_in[38]
    DIRECTION INPUT ;
    USE SIGNAL ;
    SHAPE ABUTMENT ;
    PORT
      LAYER M4 ;
      RECT 0.000 33.264 0.024 33.288 ;
    END
  END wd_in[38]
  PIN wd_in[39]
    DIRECTION INPUT ;
    USE SIGNAL ;
    SHAPE ABUTMENT ;
    PORT
      LAYER M4 ;
      RECT 0.000 33.456 0.024 33.480 ;
    END
  END wd_in[39]
  PIN wd_in[40]
    DIRECTION INPUT ;
    USE SIGNAL ;
    SHAPE ABUTMENT ;
    PORT
      LAYER M4 ;
      RECT 0.000 33.648 0.024 33.672 ;
    END
  END wd_in[40]
  PIN wd_in[41]
    DIRECTION INPUT ;
    USE SIGNAL ;
    SHAPE ABUTMENT ;
    PORT
      LAYER M4 ;
      RECT 0.000 33.840 0.024 33.864 ;
    END
  END wd_in[41]
  PIN wd_in[42]
    DIRECTION INPUT ;
    USE SIGNAL ;
    SHAPE ABUTMENT ;
    PORT
      LAYER M4 ;
      RECT 0.000 34.032 0.024 34.056 ;
    END
  END wd_in[42]
  PIN wd_in[43]
    DIRECTION INPUT ;
    USE SIGNAL ;
    SHAPE ABUTMENT ;
    PORT
      LAYER M4 ;
      RECT 0.000 34.224 0.024 34.248 ;
    END
  END wd_in[43]
  PIN wd_in[44]
    DIRECTION INPUT ;
    USE SIGNAL ;
    SHAPE ABUTMENT ;
    PORT
      LAYER M4 ;
      RECT 0.000 34.416 0.024 34.440 ;
    END
  END wd_in[44]
  PIN wd_in[45]
    DIRECTION INPUT ;
    USE SIGNAL ;
    SHAPE ABUTMENT ;
    PORT
      LAYER M4 ;
      RECT 0.000 34.608 0.024 34.632 ;
    END
  END wd_in[45]
  PIN wd_in[46]
    DIRECTION INPUT ;
    USE SIGNAL ;
    SHAPE ABUTMENT ;
    PORT
      LAYER M4 ;
      RECT 0.000 34.800 0.024 34.824 ;
    END
  END wd_in[46]
  PIN wd_in[47]
    DIRECTION INPUT ;
    USE SIGNAL ;
    SHAPE ABUTMENT ;
    PORT
      LAYER M4 ;
      RECT 0.000 34.992 0.024 35.016 ;
    END
  END wd_in[47]
  PIN wd_in[48]
    DIRECTION INPUT ;
    USE SIGNAL ;
    SHAPE ABUTMENT ;
    PORT
      LAYER M4 ;
      RECT 0.000 35.184 0.024 35.208 ;
    END
  END wd_in[48]
  PIN wd_in[49]
    DIRECTION INPUT ;
    USE SIGNAL ;
    SHAPE ABUTMENT ;
    PORT
      LAYER M4 ;
      RECT 0.000 35.376 0.024 35.400 ;
    END
  END wd_in[49]
  PIN wd_in[50]
    DIRECTION INPUT ;
    USE SIGNAL ;
    SHAPE ABUTMENT ;
    PORT
      LAYER M4 ;
      RECT 0.000 35.568 0.024 35.592 ;
    END
  END wd_in[50]
  PIN wd_in[51]
    DIRECTION INPUT ;
    USE SIGNAL ;
    SHAPE ABUTMENT ;
    PORT
      LAYER M4 ;
      RECT 0.000 35.760 0.024 35.784 ;
    END
  END wd_in[51]
  PIN wd_in[52]
    DIRECTION INPUT ;
    USE SIGNAL ;
    SHAPE ABUTMENT ;
    PORT
      LAYER M4 ;
      RECT 0.000 35.952 0.024 35.976 ;
    END
  END wd_in[52]
  PIN wd_in[53]
    DIRECTION INPUT ;
    USE SIGNAL ;
    SHAPE ABUTMENT ;
    PORT
      LAYER M4 ;
      RECT 0.000 36.144 0.024 36.168 ;
    END
  END wd_in[53]
  PIN wd_in[54]
    DIRECTION INPUT ;
    USE SIGNAL ;
    SHAPE ABUTMENT ;
    PORT
      LAYER M4 ;
      RECT 0.000 36.336 0.024 36.360 ;
    END
  END wd_in[54]
  PIN wd_in[55]
    DIRECTION INPUT ;
    USE SIGNAL ;
    SHAPE ABUTMENT ;
    PORT
      LAYER M4 ;
      RECT 0.000 36.528 0.024 36.552 ;
    END
  END wd_in[55]
  PIN wd_in[56]
    DIRECTION INPUT ;
    USE SIGNAL ;
    SHAPE ABUTMENT ;
    PORT
      LAYER M4 ;
      RECT 0.000 36.720 0.024 36.744 ;
    END
  END wd_in[56]
  PIN wd_in[57]
    DIRECTION INPUT ;
    USE SIGNAL ;
    SHAPE ABUTMENT ;
    PORT
      LAYER M4 ;
      RECT 0.000 36.912 0.024 36.936 ;
    END
  END wd_in[57]
  PIN wd_in[58]
    DIRECTION INPUT ;
    USE SIGNAL ;
    SHAPE ABUTMENT ;
    PORT
      LAYER M4 ;
      RECT 0.000 37.104 0.024 37.128 ;
    END
  END wd_in[58]
  PIN wd_in[59]
    DIRECTION INPUT ;
    USE SIGNAL ;
    SHAPE ABUTMENT ;
    PORT
      LAYER M4 ;
      RECT 0.000 37.296 0.024 37.320 ;
    END
  END wd_in[59]
  PIN wd_in[60]
    DIRECTION INPUT ;
    USE SIGNAL ;
    SHAPE ABUTMENT ;
    PORT
      LAYER M4 ;
      RECT 0.000 37.488 0.024 37.512 ;
    END
  END wd_in[60]
  PIN wd_in[61]
    DIRECTION INPUT ;
    USE SIGNAL ;
    SHAPE ABUTMENT ;
    PORT
      LAYER M4 ;
      RECT 0.000 37.680 0.024 37.704 ;
    END
  END wd_in[61]
  PIN wd_in[62]
    DIRECTION INPUT ;
    USE SIGNAL ;
    SHAPE ABUTMENT ;
    PORT
      LAYER M4 ;
      RECT 0.000 37.872 0.024 37.896 ;
    END
  END wd_in[62]
  PIN wd_in[63]
    DIRECTION INPUT ;
    USE SIGNAL ;
    SHAPE ABUTMENT ;
    PORT
      LAYER M4 ;
      RECT 0.000 38.064 0.024 38.088 ;
    END
  END wd_in[63]
  PIN addr_in[0]
    DIRECTION INPUT ;
    USE SIGNAL ;
    SHAPE ABUTMENT ;
    PORT
      LAYER M4 ;
      RECT 0.000 38.928 0.024 38.952 ;
    END
  END addr_in[0]
  PIN addr_in[1]
    DIRECTION INPUT ;
    USE SIGNAL ;
    SHAPE ABUTMENT ;
    PORT
      LAYER M4 ;
      RECT 0.000 39.120 0.024 39.144 ;
    END
  END addr_in[1]
  PIN addr_in[2]
    DIRECTION INPUT ;
    USE SIGNAL ;
    SHAPE ABUTMENT ;
    PORT
      LAYER M4 ;
      RECT 0.000 39.312 0.024 39.336 ;
    END
  END addr_in[2]
  PIN addr_in[3]
    DIRECTION INPUT ;
    USE SIGNAL ;
    SHAPE ABUTMENT ;
    PORT
      LAYER M4 ;
      RECT 0.000 39.504 0.024 39.528 ;
    END
  END addr_in[3]
  PIN addr_in[4]
    DIRECTION INPUT ;
    USE SIGNAL ;
    SHAPE ABUTMENT ;
    PORT
      LAYER M4 ;
      RECT 0.000 39.696 0.024 39.720 ;
    END
  END addr_in[4]
  PIN addr_in[5]
    DIRECTION INPUT ;
    USE SIGNAL ;
    SHAPE ABUTMENT ;
    PORT
      LAYER M4 ;
      RECT 0.000 39.888 0.024 39.912 ;
    END
  END addr_in[5]
  PIN addr_in[6]
    DIRECTION INPUT ;
    USE SIGNAL ;
    SHAPE ABUTMENT ;
    PORT
      LAYER M4 ;
      RECT 0.000 40.080 0.024 40.104 ;
    END
  END addr_in[6]
  PIN addr_in[7]
    DIRECTION INPUT ;
    USE SIGNAL ;
    SHAPE ABUTMENT ;
    PORT
      LAYER M4 ;
      RECT 0.000 40.272 0.024 40.296 ;
    END
  END addr_in[7]
  PIN addr_in[8]
    DIRECTION INPUT ;
    USE SIGNAL ;
    SHAPE ABUTMENT ;
    PORT
      LAYER M4 ;
      RECT 0.000 40.464 0.024 40.488 ;
    END
  END addr_in[8]
  PIN we_in
    DIRECTION INPUT ;
    USE SIGNAL ;
    SHAPE ABUTMENT ;
    PORT
      LAYER M4 ;
      RECT 0.000 41.328 0.024 41.352 ;
    END
  END we_in
  PIN ce_in
    DIRECTION INPUT ;
    USE SIGNAL ;
    SHAPE ABUTMENT ;
    PORT
      LAYER M4 ;
      RECT 0.000 41.520 0.024 41.544 ;
    END
  END ce_in
  PIN clk
    DIRECTION INPUT ;
    USE SIGNAL ;
    SHAPE ABUTMENT ;
    PORT
      LAYER M4 ;
      RECT 0.000 41.712 0.024 41.736 ;
    END
  END clk
  PIN VSS
    DIRECTION INOUT ;
    USE GROUND ;
    PORT
      LAYER M4 ;
      RECT 0.048 0.000 33.202 0.096 ;
      RECT 0.048 0.768 33.202 0.864 ;
      RECT 0.048 1.536 33.202 1.632 ;
      RECT 0.048 2.304 33.202 2.400 ;
      RECT 0.048 3.072 33.202 3.168 ;
      RECT 0.048 3.840 33.202 3.936 ;
      RECT 0.048 4.608 33.202 4.704 ;
      RECT 0.048 5.376 33.202 5.472 ;
      RECT 0.048 6.144 33.202 6.240 ;
      RECT 0.048 6.912 33.202 7.008 ;
      RECT 0.048 7.680 33.202 7.776 ;
      RECT 0.048 8.448 33.202 8.544 ;
      RECT 0.048 9.216 33.202 9.312 ;
      RECT 0.048 9.984 33.202 10.080 ;
      RECT 0.048 10.752 33.202 10.848 ;
      RECT 0.048 11.520 33.202 11.616 ;
      RECT 0.048 12.288 33.202 12.384 ;
      RECT 0.048 13.056 33.202 13.152 ;
      RECT 0.048 13.824 33.202 13.920 ;
      RECT 0.048 14.592 33.202 14.688 ;
      RECT 0.048 15.360 33.202 15.456 ;
      RECT 0.048 16.128 33.202 16.224 ;
      RECT 0.048 16.896 33.202 16.992 ;
      RECT 0.048 17.664 33.202 17.760 ;
      RECT 0.048 18.432 33.202 18.528 ;
      RECT 0.048 19.200 33.202 19.296 ;
      RECT 0.048 19.968 33.202 20.064 ;
      RECT 0.048 20.736 33.202 20.832 ;
      RECT 0.048 21.504 33.202 21.600 ;
      RECT 0.048 22.272 33.202 22.368 ;
      RECT 0.048 23.040 33.202 23.136 ;
      RECT 0.048 23.808 33.202 23.904 ;
      RECT 0.048 24.576 33.202 24.672 ;
      RECT 0.048 25.344 33.202 25.440 ;
      RECT 0.048 26.112 33.202 26.208 ;
      RECT 0.048 26.880 33.202 26.976 ;
      RECT 0.048 27.648 33.202 27.744 ;
      RECT 0.048 28.416 33.202 28.512 ;
      RECT 0.048 29.184 33.202 29.280 ;
      RECT 0.048 29.952 33.202 30.048 ;
      RECT 0.048 30.720 33.202 30.816 ;
      RECT 0.048 31.488 33.202 31.584 ;
      RECT 0.048 32.256 33.202 32.352 ;
      RECT 0.048 33.024 33.202 33.120 ;
      RECT 0.048 33.792 33.202 33.888 ;
      RECT 0.048 34.560 33.202 34.656 ;
      RECT 0.048 35.328 33.202 35.424 ;
      RECT 0.048 36.096 33.202 36.192 ;
      RECT 0.048 36.864 33.202 36.960 ;
      RECT 0.048 37.632 33.202 37.728 ;
      RECT 0.048 38.400 33.202 38.496 ;
      RECT 0.048 39.168 33.202 39.264 ;
      RECT 0.048 39.936 33.202 40.032 ;
      RECT 0.048 40.704 33.202 40.800 ;
      RECT 0.048 41.472 33.202 41.568 ;
    END
  END VSS
  PIN VDD
    DIRECTION INOUT ;
    USE POWER ;
    PORT
      LAYER M4 ;
      RECT 0.048 0.384 33.202 0.480 ;
      RECT 0.048 1.152 33.202 1.248 ;
      RECT 0.048 1.920 33.202 2.016 ;
      RECT 0.048 2.688 33.202 2.784 ;
      RECT 0.048 3.456 33.202 3.552 ;
      RECT 0.048 4.224 33.202 4.320 ;
      RECT 0.048 4.992 33.202 5.088 ;
      RECT 0.048 5.760 33.202 5.856 ;
      RECT 0.048 6.528 33.202 6.624 ;
      RECT 0.048 7.296 33.202 7.392 ;
      RECT 0.048 8.064 33.202 8.160 ;
      RECT 0.048 8.832 33.202 8.928 ;
      RECT 0.048 9.600 33.202 9.696 ;
      RECT 0.048 10.368 33.202 10.464 ;
      RECT 0.048 11.136 33.202 11.232 ;
      RECT 0.048 11.904 33.202 12.000 ;
      RECT 0.048 12.672 33.202 12.768 ;
      RECT 0.048 13.440 33.202 13.536 ;
      RECT 0.048 14.208 33.202 14.304 ;
      RECT 0.048 14.976 33.202 15.072 ;
      RECT 0.048 15.744 33.202 15.840 ;
      RECT 0.048 16.512 33.202 16.608 ;
      RECT 0.048 17.280 33.202 17.376 ;
      RECT 0.048 18.048 33.202 18.144 ;
      RECT 0.048 18.816 33.202 18.912 ;
      RECT 0.048 19.584 33.202 19.680 ;
      RECT 0.048 20.352 33.202 20.448 ;
      RECT 0.048 21.120 33.202 21.216 ;
      RECT 0.048 21.888 33.202 21.984 ;
      RECT 0.048 22.656 33.202 22.752 ;
      RECT 0.048 23.424 33.202 23.520 ;
      RECT 0.048 24.192 33.202 24.288 ;
      RECT 0.048 24.960 33.202 25.056 ;
      RECT 0.048 25.728 33.202 25.824 ;
      RECT 0.048 26.496 33.202 26.592 ;
      RECT 0.048 27.264 33.202 27.360 ;
      RECT 0.048 28.032 33.202 28.128 ;
      RECT 0.048 28.800 33.202 28.896 ;
      RECT 0.048 29.568 33.202 29.664 ;
      RECT 0.048 30.336 33.202 30.432 ;
      RECT 0.048 31.104 33.202 31.200 ;
      RECT 0.048 31.872 33.202 31.968 ;
      RECT 0.048 32.640 33.202 32.736 ;
      RECT 0.048 33.408 33.202 33.504 ;
      RECT 0.048 34.176 33.202 34.272 ;
      RECT 0.048 34.944 33.202 35.040 ;
      RECT 0.048 35.712 33.202 35.808 ;
      RECT 0.048 36.480 33.202 36.576 ;
      RECT 0.048 37.248 33.202 37.344 ;
      RECT 0.048 38.016 33.202 38.112 ;
      RECT 0.048 38.784 33.202 38.880 ;
      RECT 0.048 39.552 33.202 39.648 ;
      RECT 0.048 40.320 33.202 40.416 ;
      RECT 0.048 41.088 33.202 41.184 ;
      RECT 0.048 41.856 33.202 41.952 ;
    END
  END VDD
  OBS
    LAYER M1 ;
    RECT 0 0 33.250 42.000 ;
    LAYER M2 ;
    RECT 0 0 33.250 42.000 ;
    LAYER M3 ;
    RECT 0 0 33.250 42.000 ;
    LAYER M4 ;
    RECT 0 0 33.250 42.000 ;
  END
END fakeram7_512x64

END LIBRARY
